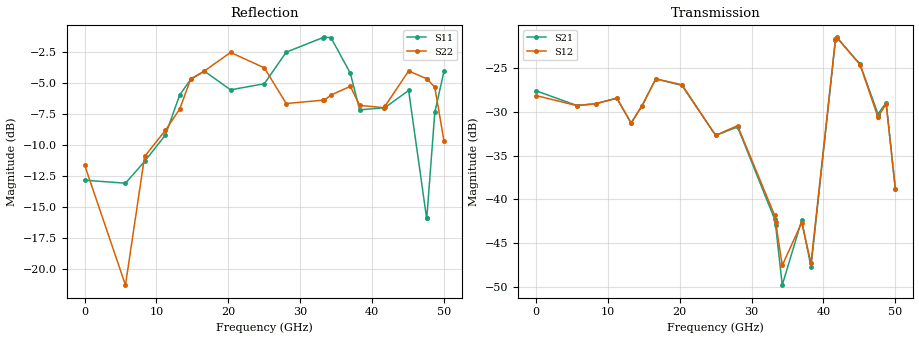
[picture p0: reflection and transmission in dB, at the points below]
!Keysight Technologies,N5245B,MY58422270,A.16.20.02
!Date: Thursday, March 05, 2026 01:37:16
!Correction: S11(C  2-Port  )
!S21(C  2-Port  )
!S12(C  2-Port  )
!S22(C  2-Port  )
!S2P File: Measurements: S11, S21, S12, S22:
# Hz S  dB  R 50
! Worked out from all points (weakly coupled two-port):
!   3201 points, 10 MHz to 50 GHz, reference 50 ohm
!   highest |S21| = -21.50 dB at 41.86 GHz (marker M1); lowest = -49.8 dB at 34.27 GHz (marker M2)
!   lowest |S11| = -15.9 dB at 47.58 GHz (marker M3), VSWR 1.38, Z = 45.2 + j14.7 ohm
!   |S11| at or under -10 dB: start of sweep to 9.79 GHz; 11.44 GHz to 11.86 GHz (421.2 MHz wide, 3.61 % of centre); 46.75 GHz to 48.31 GHz (1.564 GHz wide, 3.29 % of centre)
!   |S22| runs from -21.3 to -2.5 dB; largest |S21 - S12| = 0.0028
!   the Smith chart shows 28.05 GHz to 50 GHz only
!   S11 on the Smith chart (normalised r, x): 28.05 GHz: 0.20, +0.58; 33.19 GHz: 0.70, +2.74; 36.97 GHz: 1.51, -1.84; 47.61 GHz: 0.93, +0.31; 50 GHz: 0.53, -1.08
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1e7  -12.84 -3.3  -27.59 7.4  -28.14 8.9  -11.61 33.1
5.696362e9  -13.08 -139.5  -29.28 143.0  -29.29 143.3  -21.28 -143.0
8.352081e9  -11.33 170.1  -29.08 31.4  -29.07 31.3  -10.93 -154.9
1.125775e10  -9.20 99.4  -28.42 -72.9  -28.46 -73.1  -8.82 89.9
1.324173e10  -5.98 60.4  -31.29 -119.7  -31.27 -119.8  -7.12 -19.5
1.477267e10  -4.73 12.9  -29.31 -147.1  -29.29 -147.1  -4.69 -89.2
1.667854e10  -4.07 -44.5  -26.23 158.5  -26.23 158.1  -4.05 -141.6
2.031844e10  -5.57 -126.7  -26.99 40.8  -26.91 40.4  -2.56 154.1
2.5005e10  -5.08 171.2  -32.69 -67.6  -32.69 -68.3  -3.80 70.7
2.805127e10  -2.54 118.2  -31.73 -134.4  -31.58 -133.2  -6.67 15.0
3.319086e10  -1.36 38.1  -42.22 10.0  -41.78 8.2  -6.40 -127.0
3.334708e10  -1.35 35.5  -42.96 -0.1  -42.59 -2.6  -6.41 -130.5
3.426877e10  -1.36 19.7  -49.79 -82.1  -47.53 -93.7  -5.99 -150.4
3.697136e10  -4.24 -38.2  -42.39 92.6  -42.67 100.8  -5.29 156.2
3.826797e10  -7.18 -20.4  -47.70 99.1  -47.29 98.7  -6.82 134.4
4.167354e10  -7.01 -56.6  -21.76 -61.0  -21.63 -61.2  -7.01 113.5
4.1861e10  -6.97 -56.7  -21.50 -78.3  -21.52 -78.2  -6.83 112.3
4.507911e10  -5.62 -105.4  -24.56 87.4  -24.60 87.4  -4.05 76.0
4.757861e10  -15.89 99.5  -30.23 -13.6  -30.61 -12.5  -4.67 42.2
4.760985e10  -15.86 94.1  -30.22 -13.7  -30.55 -12.8  -4.67 41.7
4.871901e10  -7.39 -26.5  -28.96 -91.3  -29.10 -90.5  -5.36 19.6
5e10  -4.06 -78.4  -38.83 -131.0  -38.79 -132.5  -9.69 6.4
